VERSION 5.7 ;
  NOWIREEXTENSIONATPIN ON ;
  DIVIDERCHAR "/" ;
  BUSBITCHARS "[]" ;
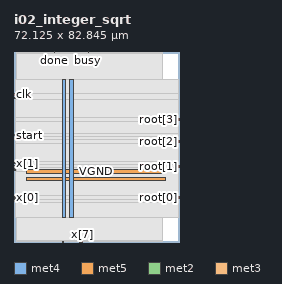
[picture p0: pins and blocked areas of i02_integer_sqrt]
MACRO i02_integer_sqrt
  CLASS BLOCK ;
  FOREIGN i02_integer_sqrt ;
  ORIGIN 0.000 0.000 ;
  SIZE 72.125 BY 82.845 ;
  PIN VGND
    DIRECTION INOUT ;
    USE GROUND ;
    PORT
      LAYER met4 ;
        RECT 24.340 10.640 25.940 70.960 ;
    END
    PORT
      LAYER met5 ;
        RECT 5.520 30.030 66.240 31.630 ;
    END
  END VGND
  PIN VPWR
    DIRECTION INOUT ;
    USE POWER ;
    PORT
      LAYER met4 ;
        RECT 21.040 10.640 22.640 70.960 ;
    END
    PORT
      LAYER met5 ;
        RECT 5.520 26.730 66.240 28.330 ;
    END
  END VPWR
  PIN busy
    DIRECTION OUTPUT ;
    USE SIGNAL ;
    ANTENNADIFFAREA 0.702900 ;
    PORT
      LAYER met2 ;
        RECT 32.290 82.565 32.570 82.845 ;
    END
  END busy
  PIN clk
    DIRECTION INPUT ;
    USE SIGNAL ;
    ANTENNAGATEAREA 0.852000 ;
    PORT
      LAYER met3 ;
        RECT 0.000 63.960 0.600 64.560 ;
    END
  END clk
  PIN done
    DIRECTION OUTPUT ;
    USE SIGNAL ;
    ANTENNADIFFAREA 0.702900 ;
    PORT
      LAYER met2 ;
        RECT 17.570 82.565 17.850 82.845 ;
    END
  END done
  PIN root[0]
    DIRECTION OUTPUT ;
    USE SIGNAL ;
    ANTENNADIFFAREA 0.702900 ;
    PORT
      LAYER met3 ;
        RECT 71.525 19.080 72.125 19.680 ;
    END
  END root[0]
  PIN root[1]
    DIRECTION OUTPUT ;
    USE SIGNAL ;
    ANTENNADIFFAREA 0.702900 ;
    PORT
      LAYER met3 ;
        RECT 71.525 32.680 72.125 33.280 ;
    END
  END root[1]
  PIN root[2]
    DIRECTION OUTPUT ;
    USE SIGNAL ;
    ANTENNADIFFAREA 0.702900 ;
    PORT
      LAYER met3 ;
        RECT 71.525 43.560 72.125 44.160 ;
    END
  END root[2]
  PIN root[3]
    DIRECTION OUTPUT ;
    USE SIGNAL ;
    ANTENNADIFFAREA 0.702900 ;
    PORT
      LAYER met3 ;
        RECT 71.525 53.080 72.125 53.680 ;
    END
  END root[3]
  PIN rst_n
    DIRECTION INPUT ;
    USE SIGNAL ;
    ANTENNAGATEAREA 0.213000 ;
    PORT
      LAYER met3 ;
        RECT 0.000 62.600 0.600 63.200 ;
    END
  END rst_n
  PIN start
    DIRECTION INPUT ;
    USE SIGNAL ;
    ANTENNAGATEAREA 0.213000 ;
    PORT
      LAYER met3 ;
        RECT 0.000 46.280 0.600 46.880 ;
    END
  END start
  PIN x[0]
    DIRECTION INPUT ;
    USE SIGNAL ;
    ANTENNAGATEAREA 0.213000 ;
    PORT
      LAYER met3 ;
        RECT 0.000 19.080 0.600 19.680 ;
    END
  END x[0]
  PIN x[1]
    DIRECTION INPUT ;
    USE SIGNAL ;
    ANTENNAGATEAREA 0.213000 ;
    PORT
      LAYER met3 ;
        RECT 0.000 34.040 0.600 34.640 ;
    END
  END x[1]
  PIN x[2]
    DIRECTION INPUT ;
    USE SIGNAL ;
    ANTENNAGATEAREA 0.213000 ;
    PORT
      LAYER met3 ;
        RECT 0.000 17.720 0.600 18.320 ;
    END
  END x[2]
  PIN x[3]
    DIRECTION INPUT ;
    USE SIGNAL ;
    ANTENNAGATEAREA 0.213000 ;
    PORT
      LAYER met3 ;
        RECT 0.000 31.320 0.600 31.920 ;
    END
  END x[3]
  PIN x[4]
    DIRECTION INPUT ;
    USE SIGNAL ;
    ANTENNAGATEAREA 0.213000 ;
    PORT
      LAYER met2 ;
        RECT 21.250 0.000 21.530 0.280 ;
    END
  END x[4]
  PIN x[5]
    DIRECTION INPUT ;
    USE SIGNAL ;
    ANTENNAGATEAREA 0.213000 ;
    PORT
      LAYER met3 ;
        RECT 0.000 32.680 0.600 33.280 ;
    END
  END x[5]
  PIN x[6]
    DIRECTION INPUT ;
    USE SIGNAL ;
    ANTENNAGATEAREA 0.213000 ;
    PORT
      LAYER met2 ;
        RECT 28.610 0.000 28.890 0.280 ;
    END
  END x[6]
  PIN x[7]
    DIRECTION INPUT ;
    USE SIGNAL ;
    ANTENNAGATEAREA 0.213000 ;
    PORT
      LAYER met2 ;
        RECT 29.530 0.000 29.810 0.280 ;
    END
  END x[7]
  OBS
      LAYER nwell ;
        RECT 5.330 10.795 66.430 70.805 ;
      LAYER li1 ;
        RECT 5.520 10.795 66.240 70.805 ;
      LAYER met1 ;
        RECT 0.990 10.640 66.240 70.960 ;
      LAYER met2 ;
        RECT 1.010 82.285 17.290 82.565 ;
        RECT 18.130 82.285 32.010 82.565 ;
        RECT 32.850 82.285 64.770 82.565 ;
        RECT 1.010 0.560 64.770 82.285 ;
        RECT 1.010 0.280 20.970 0.560 ;
        RECT 21.810 0.280 28.330 0.560 ;
        RECT 29.170 0.280 29.250 0.560 ;
        RECT 30.090 0.280 64.770 0.560 ;
      LAYER met3 ;
        RECT 0.600 64.960 71.525 70.885 ;
        RECT 1.000 62.200 71.525 64.960 ;
        RECT 0.600 54.080 71.525 62.200 ;
        RECT 0.600 52.680 71.125 54.080 ;
        RECT 0.600 47.280 71.525 52.680 ;
        RECT 1.000 45.880 71.525 47.280 ;
        RECT 0.600 44.560 71.525 45.880 ;
        RECT 0.600 43.160 71.125 44.560 ;
        RECT 0.600 35.040 71.525 43.160 ;
        RECT 1.000 33.680 71.525 35.040 ;
        RECT 1.000 32.280 71.125 33.680 ;
        RECT 1.000 30.920 71.525 32.280 ;
        RECT 0.600 20.080 71.525 30.920 ;
        RECT 1.000 18.680 71.125 20.080 ;
        RECT 1.000 17.320 71.525 18.680 ;
        RECT 0.600 10.715 71.525 17.320 ;
  END
END i02_integer_sqrt
END LIBRARY

